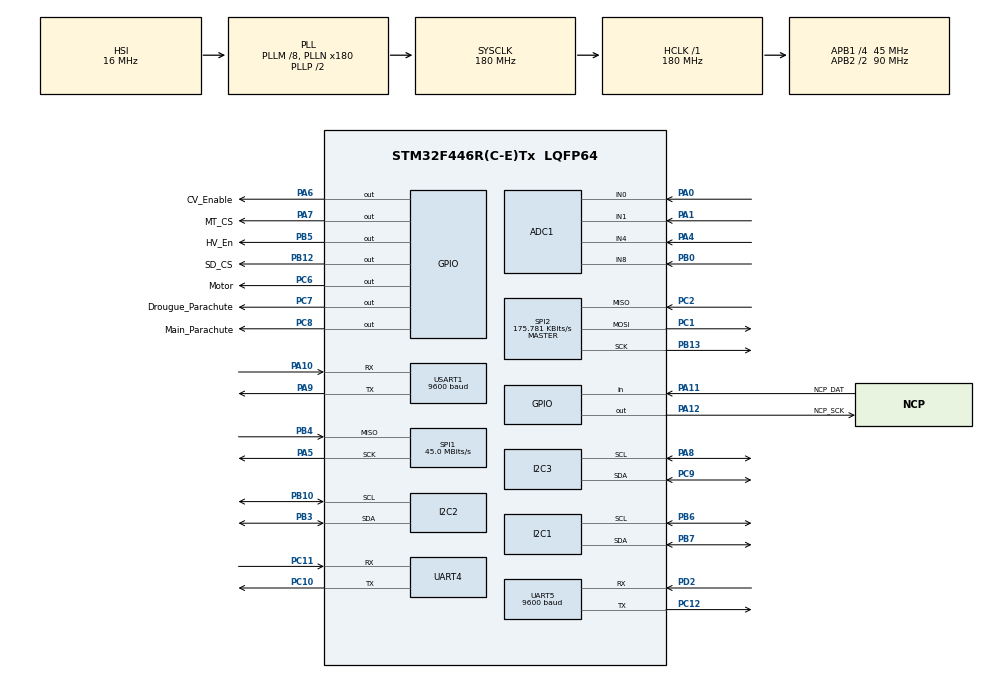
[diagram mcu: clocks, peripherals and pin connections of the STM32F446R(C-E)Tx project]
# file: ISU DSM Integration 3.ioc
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ADC1.Channel-0\#ChannelRegularConversion=ADC_CHANNEL_0
ADC1.Channel-1\#ChannelRegularConversion=ADC_CHANNEL_1
ADC1.Channel-2\#ChannelRegularConversion=ADC_CHANNEL_4
ADC1.Channel-3\#ChannelRegularConversion=ADC_CHANNEL_8
ADC1.ClockPrescaler=ADC_CLOCK_SYNC_PCLK_DIV8
ADC1.ContinuousConvMode=ENABLE
ADC1.DMAContinuousRequests=ENABLE
ADC1.NbrOfConversion=4
ADC1.NbrOfConversionFlag=1
ADC1.Rank-0\#ChannelRegularConversion=1
ADC1.Rank-1\#ChannelRegularConversion=2
ADC1.Rank-2\#ChannelRegularConversion=3
ADC1.Rank-3\#ChannelRegularConversion=4
ADC1.SamplingTime-0\#ChannelRegularConversion=ADC_SAMPLETIME_3CYCLES
ADC1.SamplingTime-1\#ChannelRegularConversion=ADC_SAMPLETIME_3CYCLES
ADC1.SamplingTime-2\#ChannelRegularConversion=ADC_SAMPLETIME_3CYCLES
ADC1.SamplingTime-3\#ChannelRegularConversion=ADC_SAMPLETIME_3CYCLES
ADC1.ScanConvMode=ENABLE
ADC1.master=1
Dma.ADC1.0.Direction=DMA_PERIPH_TO_MEMORY
Dma.ADC1.0.FIFOMode=DMA_FIFOMODE_DISABLE
Dma.ADC1.0.Instance=DMA2_Stream0
Dma.ADC1.0.MemDataAlignment=DMA_MDATAALIGN_HALFWORD
Dma.ADC1.0.MemInc=DMA_MINC_ENABLE
Dma.ADC1.0.Mode=DMA_CIRCULAR
Dma.ADC1.0.PeriphDataAlignment=DMA_PDATAALIGN_HALFWORD
Dma.ADC1.0.PeriphInc=DMA_PINC_DISABLE
Dma.ADC1.0.Priority=DMA_PRIORITY_LOW
Dma.Request0=ADC1
Dma.Request1=UART5_RX
Dma.Request2=UART5_TX
Dma.UART5_RX.1.Direction=DMA_PERIPH_TO_MEMORY
Dma.UART5_RX.1.FIFOMode=DMA_FIFOMODE_DISABLE
Dma.UART5_RX.1.Instance=DMA1_Stream0
Dma.UART5_RX.1.MemDataAlignment=DMA_MDATAALIGN_BYTE
Dma.UART5_RX.1.MemInc=DMA_MINC_ENABLE
Dma.UART5_RX.1.Mode=DMA_CIRCULAR
Dma.UART5_RX.1.PeriphDataAlignment=DMA_PDATAALIGN_BYTE
Dma.UART5_RX.1.PeriphInc=DMA_PINC_DISABLE
Dma.UART5_RX.1.Priority=DMA_PRIORITY_LOW
Dma.UART5_TX.2.Direction=DMA_MEMORY_TO_PERIPH
Dma.UART5_TX.2.FIFOMode=DMA_FIFOMODE_DISABLE
Dma.UART5_TX.2.Instance=DMA1_Stream7
Dma.UART5_TX.2.MemDataAlignment=DMA_MDATAALIGN_BYTE
Dma.UART5_TX.2.MemInc=DMA_MINC_ENABLE
Dma.UART5_TX.2.Mode=DMA_CIRCULAR
Dma.UART5_TX.2.PeriphDataAlignment=DMA_PDATAALIGN_BYTE
Dma.UART5_TX.2.PeriphInc=DMA_PINC_DISABLE
Dma.UART5_TX.2.Priority=DMA_PRIORITY_LOW
FATFS._MAX_SS=4096
FATFS._USE_LFN=1
Mcu.Family=STM32F4
Mcu.Name=STM32F446R(C-E)Tx
Mcu.Package=LQFP64
NVIC.DMA1_Stream0_IRQn=true\:0\:0\:false\:false\:true\:false\:true\:true
NVIC.DMA1_Stream7_IRQn=true\:0\:0\:false\:false\:true\:false\:true\:true
NVIC.DMA2_Stream0_IRQn=true\:0\:0\:false\:false\:true\:false\:true\:true
NVIC.PriorityGroup=NVIC_PRIORITYGROUP_4
NVIC.RCC_IRQn=true\:0\:0\:false\:false\:true\:true\:false\:true
NVIC.UART5_IRQn=true\:0\:0\:false\:false\:true\:true\:true\:true
NVIC.USART1_IRQn=true\:0\:0\:false\:false\:true\:true\:true\:true
PA0-WKUP.Signal=ADCx_IN0
PA1.Signal=ADCx_IN1
PA10.Mode=Asynchronous
PA10.Signal=USART1_RX
PA11.GPIO_Label=NCP_DAT
PA11.Signal=GPIO_Input
PA12.GPIO_Label=NCP_SCK
PA12.Signal=GPIO_Output
PA4.Signal=ADCx_IN4
PA5.Mode=RX_Only_Simplex_Unidirect_Master
PA5.Signal=SPI1_SCK
PA6.GPIO_Label=CV_Enable
PA6.GPIO_PuPd=GPIO_PULLDOWN
PA6.Signal=GPIO_Output
PA7.GPIO_Label=MT_CS
PA7.Signal=GPIO_Output
PA8.Mode=I2C
PA8.Signal=I2C3_SCL
PA9.Mode=Asynchronous
PA9.Signal=USART1_TX
PB0.Signal=ADCx_IN8
PB10.Mode=I2C
PB10.Signal=I2C2_SCL
PB12.GPIO_Label=SD_CS
PB12.Signal=GPIO_Output
PB13.Mode=Full_Duplex_Master
PB13.Signal=SPI2_SCK
PB3.Mode=I2C
PB3.Signal=I2C2_SDA
PB4.Mode=RX_Only_Simplex_Unidirect_Master
PB4.Signal=SPI1_MISO
PB5.GPIO_Label=HV_En
PB5.Signal=GPIO_Output
PB6.Mode=I2C
PB6.Signal=I2C1_SCL
PB7.Mode=I2C
PB7.Signal=I2C1_SDA
PC1.Mode=Full_Duplex_Master
PC1.Signal=SPI2_MOSI
PC10.Mode=Asynchronous
PC10.Signal=UART4_TX
PC11.Mode=Asynchronous
PC11.Signal=UART4_RX
PC12.Mode=Asynchronous
PC12.Signal=UART5_TX
PC14-OSC32_IN.Mode=LSE-External-Oscillator
PC14-OSC32_IN.Signal=RCC_OSC32_IN
PC15-OSC32_OUT.Mode=LSE-External-Oscillator
PC15-OSC32_OUT.Signal=RCC_OSC32_OUT
PC2.Mode=Full_Duplex_Master
PC2.Signal=SPI2_MISO
PC6.GPIO_Label=Motor
PC6.GPIO_PuPd=GPIO_PULLDOWN
PC6.Signal=GPIO_Output
PC7.GPIO_Label=Drougue_Parachute
PC7.GPIO_PuPd=GPIO_PULLDOWN
PC7.Signal=GPIO_Output
PC8.GPIO_Label=Main_Parachute
PC8.GPIO_PuPd=GPIO_PULLDOWN
PC8.Signal=GPIO_Output
PC9.Mode=I2C
PC9.Signal=I2C3_SDA
PD2.Mode=Asynchronous
PD2.Signal=UART5_RX
PH0-OSC_IN.Mode=HSE-External-Oscillator
PH0-OSC_IN.Signal=RCC_OSC_IN
PH1-OSC_OUT.Mode=HSE-External-Oscillator
PH1-OSC_OUT.Signal=RCC_OSC_OUT
ProjectManager.HeapSize=0x400
ProjectManager.StackSize=0x800
ProjectManager.TargetToolchain=STM32CubeIDE
RCC.AHBFreq_Value=180000000
RCC.APB1CLKDivider=RCC_HCLK_DIV4
RCC.APB1Freq_Value=45000000
RCC.APB1TimFreq_Value=90000000
RCC.APB2CLKDivider=RCC_HCLK_DIV2
RCC.APB2Freq_Value=90000000
RCC.APB2TimFreq_Value=180000000
RCC.CortexFreq_Value=180000000
RCC.HCLKFreq_Value=180000000
RCC.HSE_VALUE=8000000
RCC.PLLM=8
RCC.PLLN=180
RCC.SYSCLKFreq_VALUE=180000000
RCC.SYSCLKSource=RCC_SYSCLKSOURCE_PLLCLK
RCC.USBFreq_Value=180000000
RCC.VCOOutputFreq_Value=360000000
SH.ADCx_IN0.0=ADC1_IN0,IN0
SH.ADCx_IN1.0=ADC1_IN1,IN1
SH.ADCx_IN4.0=ADC1_IN4,IN4
SH.ADCx_IN8.0=ADC1_IN8,IN8
SPI1.CalculateBaudRate=45.0 MBits/s
SPI1.Direction=SPI_DIRECTION_2LINES_RXONLY
SPI1.Mode=SPI_MODE_MASTER
SPI1.VirtualType=VM_MASTER
SPI2.BaudRatePrescaler=SPI_BAUDRATEPRESCALER_256
SPI2.CalculateBaudRate=175.781 KBits/s
SPI2.Direction=SPI_DIRECTION_2LINES
SPI2.Mode=SPI_MODE_MASTER
SPI2.VirtualType=VM_MASTER
TIM1.Prescaler=45000
UART4.VirtualMode=Asynchronous
UART5.BaudRate=9600
UART5.VirtualMode=Asynchronous
USART1.BaudRate=9600
USART1.VirtualMode=VM_ASYNC
VP_FATFS_VS_Generic.Mode=User_defined
VP_TIM1_VS_ClockSourceINT.Mode=Internal
board=custom

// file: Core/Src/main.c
/* USER CODE BEGIN Header */
/**
  ******************************************************************************
  * @file           : main.c
  * @brief          : Main program body
  ******************************************************************************
  * @attention
  *
  * Copyright (c) 2023 STMicroelectronics.
  * All rights reserved.
  *
  * This software is licensed under terms that can be found in the LICENSE file
  * in the root directory of this software component.
  * If no LICENSE file comes with this software, it is provided AS-IS.
  *
  ******************************************************************************
  */
/* USER CODE END Header */
#include "main.h"
#include "fatfs.h"

/* USER CODE BEGIN Includes */
#include <stdbool.h>
#include "math.h"
#include "mpu6050.h"
#include "MAX6675.h"
#include "uartRingBuffer.h"
#include "NMEA.h"
#include "BMP180.h"
#include "HX710B.h"
#include "DataPacket.h"
#include "RTC.h"
#include "fatfs_sd.h"
#include "stdio.h"
/* USER CODE END Includes */

/* USER CODE BEGIN PD */
#define CV_En_Pin GPIO_PIN_6
/* USER CODE END PD */

ADC_HandleTypeDef hadc1;
DMA_HandleTypeDef hdma_adc1;

I2C_HandleTypeDef hi2c1;
I2C_HandleTypeDef hi2c2;
I2C_HandleTypeDef hi2c3;

SPI_HandleTypeDef hspi1;
SPI_HandleTypeDef hspi2;

TIM_HandleTypeDef htim1;

UART_HandleTypeDef huart4;
UART_HandleTypeDef huart5;
extern UART_HandleTypeDef huart1;
DMA_HandleTypeDef hdma_uart5_rx;
DMA_HandleTypeDef hdma_uart5_tx;

/* USER CODE BEGIN PV */
bool pds_flag = 1;
char rx_data[2];
char tx_data[2];
float Ax, Ay, Az, Gx, Gy, Gz, Avg1, Avg2;

uint8_t err_gyro = 0;

float CpmVoltage = 0.0;
float HVoltage = 0.0;
bool En_Voltage_ui=0;

float temperature;
uint16_t timer_val=0;

uint16_t dmaOut[4];

//Barometer_Sensor
float Temperature2;
float Pressure;
float Altitude;

//current_sensor 5A
uint16_t readValue5;
float rawVoltage5;
float current5;
float sensitivity5 = 0.185;
float adc_err5=1.052;

//current_sensor 20A
uint16_t readValue20;
float rawVoltage20;
float current20;
float sensitivity20 = 0.1;
float adc_err20=1.052;

//GPS Data
char GGA[100];
char RMC[100];

//Fall Detection
bool tilt=0;
bool fall=false;
bool pds=0;
GPSSTRUCT gpsData;

//Nose Cone Pressure
uint16_t NCPressure=0;

TIME_Handle time;
TIME_Handle timein;

uint8_t settime=0;

char TxBuff[150];
char tempbuff[6];

union Transmission trans1;

FATFS fs;  // file system
FIL fil; // File
FILINFO fno;
FRESULT fresult;  // result
UINT br, bw;  // File read/write count

/**** capacity related *****/
FATFS *pfs;
DWORD fre_clust;
uint32_t total, free_space;

#define BUFFER_SIZE 128
char buffer[BUFFER_SIZE];  // to store strings..
char rxbuffer[BUFFER_SIZE];

int writepos=0;

char tx_data[2];
/* USER CODE END PV */

void SystemClock_Config(void);
static void MX_GPIO_Init(void);
static void MX_DMA_Init(void);
static void MX_ADC1_Init(void);
static void MX_SPI1_Init(void);
static void MX_TIM1_Init(void);
static void MX_USART1_UART_Init(void);
static void MX_I2C1_Init(void);
static void MX_I2C2_Init(void);
static void MX_UART4_Init(void);
static void MX_I2C3_Init(void);
static void MX_SPI2_Init(void);
static void MX_UART5_Init(void);

/* USER CODE BEGIN 0 */

int bufsize (char *buf)
{
	int i=0;
	while (*buf++ != '\0') i++;
	return i;
}

void clear_buffer (void)
{
	for (int i=0; i<BUFFER_SIZE; i++) buffer[i] = '\0';
}
/* USER CODE END 0 */

int main(void)
{
  /* USER CODE BEGIN 1 */
	timein.seconds = 0;

  /* USER CODE END 1 */

  /* MCU Configuration--------------------------------------------------------*/

  /* Reset of all peripherals, Initializes the Flash interface and the Systick. */
  HAL_Init();

  /* Configure the system clock */
  SystemClock_Config();

  /* Initialize all configured peripherals */
  MX_GPIO_Init();
  MX_DMA_Init();
  MX_ADC1_Init();
  MX_SPI1_Init();
  MX_TIM1_Init();
  MX_USART1_UART_Init();
  MX_I2C1_Init();
  MX_I2C2_Init();
  MX_UART4_Init();
  MX_I2C3_Init();
  MX_SPI2_Init();
  MX_FATFS_Init();
  MX_UART5_Init();
  /* USER CODE BEGIN 2 */

  HAL_UART_Receive_DMA(&huart5,rx_data, sizeof(rx_data));

  HAL_ADC_Init(&hadc1);
  MPU6050_Init();
  HAL_ADC_Start_DMA(&hadc1, dmaOut, 4);
  BMP180_Start();

  Ringbuf_init();
  HAL_Delay(500);

  if(settime==1)
      Set_Time(timein.seconds, timein.minutes, timein.hour , timein.dayofweek, timein.dayofmonth, timein.month, timein.year);

  void current_sensor5()
  {
  	  readValue5 = dmaOut[1];
  	  rawVoltage5 = ((float) readValue5 * 3.3) / 4095 *adc_err5;
  	  trans1.tlm1.CPM_Current =(1 - rawVoltage5)/sensitivity5;
  }

  void current_sensor20()
  {
  	  readValue20 = dmaOut[2];
  	  rawVoltage20 = ((float) readValue20 * 3.3) / 4095 *adc_err20;
  	  trans1.tlm1.H_Current =(1 - rawVoltage20)/sensitivity20;
  }

  void barometer_sensor()
  {
  	  Temperature2 = BMP180_GetTemp();
  	  Pressure = BMP180_GetPress(0);
  	  trans1.tlm1.Altitude = BMP180_GetAlt(0);
  }
void isu_check()
{
	;
}
  strcpy(buffer,"Hello Duta'h\n");

  /* USER CODE END 2 */

  /* Infinite loop */
  /* USER CODE BEGIN WHILE */
  while (1)
  {
	  /*if(rx_data[0]=='T')
	  {
		 HAL_GPIO_WritePin(GPIOC, GPIO_PIN_6, 1);
				 HAL_GPIO_WritePin(GPIOC, GPIO_PIN_7, 1);
				 HAL_GPIO_WritePin(GPIOC, GPIO_PIN_8, 1);
	  }*/
	  switch(rx_data[0])
	  	  {
	      case 'N': //Initialization
		  memset(tx_data,'S',2);
	  	  HAL_UART_Transmit(&huart5, tx_data, sizeof(tx_data), 100);
	  	  break;
	  	  case 'K': //Standby
	  	  memset(tx_data,'J',2);
	  	  HAL_UART_Transmit(&huart5, tx_data, sizeof(tx_data), 100);
	  	  break;
	  	  case 'A': //Arming
	  	  memset(tx_data,'B',2);
	  	  HAL_UART_Transmit(&huart5, tx_data, sizeof(tx_data), 100);
	  	  isu_check();
	  	  break;
	  	  memset(tx_data,'D',2);
	  	  HAL_UART_Transmit(&huart5, tx_data, sizeof(tx_data), 100);
	  	  case 'I': //Launching
	  	  memset(tx_data,'L',2);
	  	  HAL_UART_Transmit(&huart5, tx_data, sizeof(tx_data), 100);
	  	  HAL_GPIO_WritePin(GPIOC, GPIO_PIN_6, 1);
	  	  memset(tx_data,'\0',2);
	  	  break;
	  	  case 'Y': //Kill_Switch
	  	  HAL_GPIO_WritePin(GPIOC, GPIO_PIN_6, 0);
	  	  memset(tx_data,'E',2);
	  	  HAL_UART_Transmit(&huart5, tx_data, sizeof(tx_data), 100);
	  	  break;
	  	  case 'F': //Error
	  	  memset(tx_data,'E',2);
	  	  HAL_UART_Transmit(&huart5, tx_data, sizeof(tx_data), 100);
	  	  break;
	  	  default:
	  	  memset(tx_data,'\0',2);
	  	  HAL_UART_Transmit(&huart5, tx_data, sizeof(tx_data), 100);
	  	  }
   HAL_Delay(5);
	  if(Wait_for("GGA")==1)
	  {
		  Copy_upto("*", GGA);
		  decodeGGA(GGA, &gpsData.ggastruct);
	  }
	  if (Wait_for("RMC")==1)
	  {
		  Copy_upto("*",RMC);
		  decodeRMC(RMC, &gpsData.rmcstruct);
	  }

	  trans1.tlm1.M_Temp=Max6675_Read_Temp();
	  barometer_sensor();
	  trans1.tlm1.NC_Press =readHX();

	  current_sensor5();
	  current_sensor20();

	  MPU6050_Read_Accel (&Ax, &Ay, &Az);
	  MPU6050_Read_Gyro(&Gx, &Gy, &Gz);
	  //Fall Detection
	 	  Avg1 = pow(pow(Ax,2)+pow(Ay,2)+pow(Az,2),0.5);
	 	  Avg2 = pow(pow(Gx,2)+pow(Gy,2)+pow(Gz,2),0.5);
	 	  tilt= HAL_GPIO_ReadPin(GPIOC, GPIO_PIN_3); //tilt_sensor
	 	  if(((Avg1 >= 1 && Avg2 >= 30) && tilt==0) || fall==true)
	 	  {
	 		  HAL_GPIO_WritePin(GPIOC, GPIO_PIN_8, GPIO_PIN_SET); //Trigger PDS(Main Parachute)
	 		  HAL_GPIO_WritePin(GPIOA, GPIO_PIN_5, 1);
	 	  }
	 	  else
	 	  {
	 	  }
	 	  HAL_Delay (100);  // wait for a while
	 	  //PDS_read_sensor
	 	  pds = HAL_GPIO_ReadPin(GPIOC, GPIO_PIN_5);
	 	  if(pds==0)
	 	  {
	 		  HAL_GPIO_WritePin(GPIOC, GPIO_PIN_8, GPIO_PIN_RESET); //Trigger PDS(Main Parachute)
	 		  if(pds_flag==1){
	 			  memset(tx_data,'R',2);
	 			  HAL_UART_Transmit(&huart5, tx_data, sizeof(tx_data), 100);
	 			  HAL_Delay(3000);
	 			  memset(tx_data,'\0',2);
	 			  pds_flag=0;
	 		  }
	 	  }
	  //HAL_Delay(250);
	  trans1.tlm1.Ax=Ax;
	  trans1.tlm1.Ay=Ay;
	  trans1.tlm1.Az=Az;
	  trans1.tlm1.Gx=Gx;
	  trans1.tlm1.Gy=Gy;
	  trans1.tlm1.Gz=Gz;

	  HAL_GPIO_WritePin(GPIOA, CV_En_Pin, 1);
	  trans1.tlm1.CPM_Voltage = dmaOut[0]*(5.0/4096.0);
	  HAL_GPIO_WritePin(HV_En_GPIO_Port, HV_En_Pin, 1);
	  trans1.tlm1.H_Voltage=dmaOut[3]*(9.36/4096);

	  HAL_Delay(100);
	  Get_Time();
		trans1.tlm1.seconds=time.seconds;
		trans1.tlm1.minutes=time.minutes;
		trans1.tlm1.hour=time.hour;
		trans1.tlm1.dayofmonth=time.dayofmonth;
		trans1.tlm1.month=time.month;
		trans1.tlm1.year=time.year;

		fresult = f_mount(&fs, "/", 1);
		HAL_Delay(500);
		fresult = f_open(&fil, "testfile.txt", FA_OPEN_ALWAYS | FA_READ | FA_WRITE);
		//	  memset(TxBuff,"\0",150);

	  for(int i=0; i<23; i++)
	  {

		  memset(tempbuff,'\0',6);
		  gcvt(trans1.dataframe[i],4,tempbuff);
		  //strcat(TxBuff,tempbuff);
		  strcat(tempbuff,",");
		  HAL_UART_Transmit(&huart4, tempbuff, strlen(tempbuff), 100);
		  if(i==22) strcat(tempbuff, "\n");

		  f_lseek(&fil,writepos);
		  fresult = f_write(&fil, tempbuff, bufsize(tempbuff), &bw);
		  writepos+=bufsize(tempbuff);
	  }
//		HAL_UART_Transmit(&huart4, "20-11-2023,", 11, 100);
//		memset(tempbuff,'\0',6);
//		gcvt(trans1.tlm1.Ax,4,tempbuff);
//		strcat(tempbuff,",");
//		HAL_UART_Transmit(&huart4, tempbuff, strlen(tempbuff), 100);
//		memset(tempbuff,'\0',6);
//		strcat(tempbuff,",");
//		gcvt(trans1.tlm1.Ay,4,tempbuff);
//		strcat(tempbuff,",");
//		HAL_UART_Transmit(&huart4, tempbuff, strlen(tempbuff), 100);
//		memset(tempbuff,'\0',6);
//		gcvt(trans1.tlm1.Az,4,tempbuff);
//		strcat(tempbuff,",");
//		HAL_UART_Transmit(&huart4, tempbuff, strlen(tempbuff), 100);
//		HAL_UART_Transmit(&huart4, "9.25,", 6, 100);
//		HAL_UART_Transmit(&huart4, "0.01,", 6, 100);
//		gcvt(trans1.tlm1.CPM_Voltage,4,tempbuff);
//		strcat(tempbuff,",");
//		HAL_UART_Transmit(&huart4, tempbuff, strlen(tempbuff), 100);
//		gcvt(trans1.tlm1.CPM_Current,4,tempbuff);
//		strcat(tempbuff,",");
//		HAL_UART_Transmit(&huart4, tempbuff, strlen(tempbuff), 100);
//		HAL_UART_Transmit(&huart4, "22.4,", 7, 100);
//		memset(tempbuff,'\0',6);
//		gcvt(trans1.tlm1.Altitude,4,tempbuff);
//		strcat(tempbuff,",");
//		HAL_UART_Transmit(&huart4, tempbuff, strlen(tempbuff), 100);
//		memset(tempbuff,'\0',6);
//		gcvt(Pressure,4,tempbuff);
//		strcat(tempbuff,",");
//		HAL_UART_Transmit(&huart4, tempbuff, strlen(tempbuff), 100);
//		HAL_UART_Transmit(&huart4, "0,", 3, 100);
//		memset(tempbuff,'\0',6);
//		gcvt(trans1.tlm1.Gx,4,tempbuff);
//		strcat(tempbuff,",");
//		HAL_UART_Transmit(&huart4, tempbuff, strlen(tempbuff), 100);
//		memset(tempbuff,'\0',6);
//		gcvt(trans1.tlm1.Gy,4,tempbuff);
//		strcat(tempbuff,",");
//		HAL_UART_Transmit(&huart4, tempbuff, strlen(tempbuff), 100);
//		memset(tempbuff,'\0',6);
//		gcvt(trans1.tlm1.Gz,4,tempbuff);
//		strcat(tempbuff,",");
//		HAL_UART_Transmit(&huart4, tempbuff, strlen(tempbuff), 100);
//		HAL_UART_Transmit(&huart4, "0,", 3, 100);
//		HAL_UART_Transmit(&huart4, "0", 3, 100);

	  f_close(&fil);
	  fresult = f_mount(NULL, "/", 1);

	  HAL_UART_Transmit(&huart4, "\n", 1, 100);

	  /*fresult = f_lseek(&fil, writepos);
	  fresult = f_write(&fil, strw, bufsize(strw), &bw);
	  f_close(&fil);
	  writepos+=sizeof(strw);

	  fresult = f_open(&fil, "testfile.txt", FA_READ);
	  f_read (&fil, rxbuffer, f_size(&fil), &br);
	  f_close(&fil);
	  fresult = f_mount(NULL, "/", 1);*/

	  HAL_Delay(100);

    /* USER CODE END WHILE */

  }
}

void SystemClock_Config(void)
{
  RCC_OscInitTypeDef RCC_OscInitStruct = {0};
  RCC_ClkInitTypeDef RCC_ClkInitStruct = {0};

  /** Configure the main internal regulator output voltage
  */
  __HAL_RCC_PWR_CLK_ENABLE();
  __HAL_PWR_VOLTAGESCALING_CONFIG(PWR_REGULATOR_VOLTAGE_SCALE1);

  /** Initializes the RCC Oscillators according to the specified parameters
  * in the RCC_OscInitTypeDef structure.
  */
  RCC_OscInitStruct.OscillatorType = RCC_OSCILLATORTYPE_HSI;
  RCC_OscInitStruct.HSIState = RCC_HSI_ON;
  RCC_OscInitStruct.HSICalibrationValue = RCC_HSICALIBRATION_DEFAULT;
  RCC_OscInitStruct.PLL.PLLState = RCC_PLL_ON;
  RCC_OscInitStruct.PLL.PLLSource = RCC_PLLSOURCE_HSI;
  RCC_OscInitStruct.PLL.PLLM = 8;
  RCC_OscInitStruct.PLL.PLLN = 180;
  RCC_OscInitStruct.PLL.PLLP = RCC_PLLP_DIV2;
  RCC_OscInitStruct.PLL.PLLQ = 2;
  RCC_OscInitStruct.PLL.PLLR = 2;
  if (HAL_RCC_OscConfig(&RCC_OscInitStruct) != HAL_OK)
  {
    Error_Handler();
  }

  /** Activate the Over-Drive mode
  */
  if (HAL_PWREx_EnableOverDrive() != HAL_OK)
  {
    Error_Handler();
  }

  /** Initializes the CPU, AHB and APB buses clocks
  */
  RCC_ClkInitStruct.ClockType = RCC_CLOCKTYPE_HCLK|RCC_CLOCKTYPE_SYSCLK
                              |RCC_CLOCKTYPE_PCLK1|RCC_CLOCKTYPE_PCLK2;
  RCC_ClkInitStruct.SYSCLKSource = RCC_SYSCLKSOURCE_PLLCLK;
  RCC_ClkInitStruct.AHBCLKDivider = RCC_SYSCLK_DIV1;
  RCC_ClkInitStruct.APB1CLKDivider = RCC_HCLK_DIV4;
  RCC_ClkInitStruct.APB2CLKDivider = RCC_HCLK_DIV2;

  if (HAL_RCC_ClockConfig(&RCC_ClkInitStruct, FLASH_LATENCY_5) != HAL_OK)
  {
    Error_Handler();
  }
}

static void MX_ADC1_Init(void)
{

  ADC_ChannelConfTypeDef sConfig = {0};

  /** Configure the global features of the ADC (Clock, Resolution, Data Alignment and number of conversion)
  */
  hadc1.Instance = ADC1;
  hadc1.Init.ClockPrescaler = ADC_CLOCK_SYNC_PCLK_DIV8;
  hadc1.Init.Resolution = ADC_RESOLUTION_12B;
  hadc1.Init.ScanConvMode = ENABLE;
  hadc1.Init.ContinuousConvMode = ENABLE;
  hadc1.Init.DiscontinuousConvMode = DISABLE;
  hadc1.Init.ExternalTrigConvEdge = ADC_EXTERNALTRIGCONVEDGE_NONE;
  hadc1.Init.ExternalTrigConv = ADC_SOFTWARE_START;
  hadc1.Init.DataAlign = ADC_DATAALIGN_RIGHT;
  hadc1.Init.NbrOfConversion = 4;
  hadc1.Init.DMAContinuousRequests = ENABLE;
  hadc1.Init.EOCSelection = ADC_EOC_SINGLE_CONV;
  if (HAL_ADC_Init(&hadc1) != HAL_OK)
  {
    Error_Handler();
  }

  /** Configure for the selected ADC regular channel its corresponding rank in the sequencer and its sample time.
  */
  sConfig.Channel = ADC_CHANNEL_0;
  sConfig.Rank = 1;
  sConfig.SamplingTime = ADC_SAMPLETIME_3CYCLES;
  if (HAL_ADC_ConfigChannel(&hadc1, &sConfig) != HAL_OK)
  {
    Error_Handler();
  }

  /** Configure for the selected ADC regular channel its corresponding rank in the sequencer and its sample time.
  */
  sConfig.Channel = ADC_CHANNEL_1;
  sConfig.Rank = 2;
  if (HAL_ADC_ConfigChannel(&hadc1, &sConfig) != HAL_OK)
  {
    Error_Handler();
  }

  /** Configure for the selected ADC regular channel its corresponding rank in the sequencer and its sample time.
  */
  sConfig.Channel = ADC_CHANNEL_4;
  sConfig.Rank = 3;
  if (HAL_ADC_ConfigChannel(&hadc1, &sConfig) != HAL_OK)
  {
    Error_Handler();
  }

  /** Configure for the selected ADC regular channel its corresponding rank in the sequencer and its sample time.
  */
  sConfig.Channel = ADC_CHANNEL_8;
  sConfig.Rank = 4;
  if (HAL_ADC_ConfigChannel(&hadc1, &sConfig) != HAL_OK)
  {
    Error_Handler();
  }

}

static void MX_I2C1_Init(void)
{

  hi2c1.Instance = I2C1;
  hi2c1.Init.ClockSpeed = 100000;
  hi2c1.Init.DutyCycle = I2C_DUTYCYCLE_2;
  hi2c1.Init.OwnAddress1 = 0;
  hi2c1.Init.AddressingMode = I2C_ADDRESSINGMODE_7BIT;
  hi2c1.Init.DualAddressMode = I2C_DUALADDRESS_DISABLE;
  hi2c1.Init.OwnAddress2 = 0;
  hi2c1.Init.GeneralCallMode = I2C_GENERALCALL_DISABLE;
  hi2c1.Init.NoStretchMode = I2C_NOSTRETCH_DISABLE;
  if (HAL_I2C_Init(&hi2c1) != HAL_OK)
  {
    Error_Handler();
  }

}

static void MX_I2C2_Init(void)
{

  hi2c2.Instance = I2C2;
  hi2c2.Init.ClockSpeed = 100000;
  hi2c2.Init.DutyCycle = I2C_DUTYCYCLE_2;
  hi2c2.Init.OwnAddress1 = 0;
  hi2c2.Init.AddressingMode = I2C_ADDRESSINGMODE_7BIT;
  hi2c2.Init.DualAddressMode = I2C_DUALADDRESS_DISABLE;
  hi2c2.Init.OwnAddress2 = 0;
  hi2c2.Init.GeneralCallMode = I2C_GENERALCALL_DISABLE;
  hi2c2.Init.NoStretchMode = I2C_NOSTRETCH_DISABLE;
  if (HAL_I2C_Init(&hi2c2) != HAL_OK)
  {
    Error_Handler();
  }

}

static void MX_I2C3_Init(void)
{

  hi2c3.Instance = I2C3;
  hi2c3.Init.ClockSpeed = 100000;
  hi2c3.Init.DutyCycle = I2C_DUTYCYCLE_2;
  hi2c3.Init.OwnAddress1 = 0;
  hi2c3.Init.AddressingMode = I2C_ADDRESSINGMODE_7BIT;
  hi2c3.Init.DualAddressMode = I2C_DUALADDRESS_DISABLE;
  hi2c3.Init.OwnAddress2 = 0;
  hi2c3.Init.GeneralCallMode = I2C_GENERALCALL_DISABLE;
  hi2c3.Init.NoStretchMode = I2C_NOSTRETCH_DISABLE;
  if (HAL_I2C_Init(&hi2c3) != HAL_OK)
  {
    Error_Handler();
  }

}

static void MX_SPI1_Init(void)
{

  /* SPI1 parameter configuration*/
  hspi1.Instance = SPI1;
  hspi1.Init.Mode = SPI_MODE_MASTER;
  hspi1.Init.Direction = SPI_DIRECTION_2LINES_RXONLY;
  hspi1.Init.DataSize = SPI_DATASIZE_8BIT;
  hspi1.Init.CLKPolarity = SPI_POLARITY_LOW;
  hspi1.Init.CLKPhase = SPI_PHASE_1EDGE;
  hspi1.Init.NSS = SPI_NSS_SOFT;
  hspi1.Init.BaudRatePrescaler = SPI_BAUDRATEPRESCALER_2;
  hspi1.Init.FirstBit = SPI_FIRSTBIT_MSB;
  hspi1.Init.TIMode = SPI_TIMODE_DISABLE;
  hspi1.Init.CRCCalculation = SPI_CRCCALCULATION_DISABLE;
  hspi1.Init.CRCPolynomial = 10;
  if (HAL_SPI_Init(&hspi1) != HAL_OK)
  {
    Error_Handler();
  }

}

static void MX_SPI2_Init(void)
{

  /* SPI2 parameter configuration*/
  hspi2.Instance = SPI2;
  hspi2.Init.Mode = SPI_MODE_MASTER;
  hspi2.Init.Direction = SPI_DIRECTION_2LINES;
  hspi2.Init.DataSize = SPI_DATASIZE_8BIT;
  hspi2.Init.CLKPolarity = SPI_POLARITY_LOW;
  hspi2.Init.CLKPhase = SPI_PHASE_1EDGE;
  hspi2.Init.NSS = SPI_NSS_SOFT;
  hspi2.Init.BaudRatePrescaler = SPI_BAUDRATEPRESCALER_256;
  hspi2.Init.FirstBit = SPI_FIRSTBIT_MSB;
  hspi2.Init.TIMode = SPI_TIMODE_DISABLE;
  hspi2.Init.CRCCalculation = SPI_CRCCALCULATION_DISABLE;
  hspi2.Init.CRCPolynomial = 10;
  if (HAL_SPI_Init(&hspi2) != HAL_OK)
  {
    Error_Handler();
  }

}

static void MX_TIM1_Init(void)
{

  TIM_ClockConfigTypeDef sClockSourceConfig = {0};
  TIM_MasterConfigTypeDef sMasterConfig = {0};

  htim1.Instance = TIM1;
  htim1.Init.Prescaler = 45000;
  htim1.Init.CounterMode = TIM_COUNTERMODE_UP;
  htim1.Init.Period = 65535;
  htim1.Init.ClockDivision = TIM_CLOCKDIVISION_DIV1;
  htim1.Init.RepetitionCounter = 0;
  htim1.Init.AutoReloadPreload = TIM_AUTORELOAD_PRELOAD_DISABLE;
  if (HAL_TIM_Base_Init(&htim1) != HAL_OK)
  {
    Error_Handler();
  }
  sClockSourceConfig.ClockSource = TIM_CLOCKSOURCE_INTERNAL;
  if (HAL_TIM_ConfigClockSource(&htim1, &sClockSourceConfig) != HAL_OK)
  {
    Error_Handler();
  }
  sMasterConfig.MasterOutputTrigger = TIM_TRGO_RESET;
  sMasterConfig.MasterSlaveMode = TIM_MASTERSLAVEMODE_DISABLE;
  if (HAL_TIMEx_MasterConfigSynchronization(&htim1, &sMasterConfig) != HAL_OK)
  {
    Error_Handler();
  }

}

static void MX_UART4_Init(void)
{

  huart4.Instance = UART4;
  huart4.Init.BaudRate = 115200;
  huart4.Init.WordLength = UART_WORDLENGTH_8B;
  huart4.Init.StopBits = UART_STOPBITS_1;
  huart4.Init.Parity = UART_PARITY_NONE;
  huart4.Init.Mode = UART_MODE_TX_RX;
  huart4.Init.HwFlowCtl = UART_HWCONTROL_NONE;
  huart4.Init.OverSampling = UART_OVERSAMPLING_16;
  if (HAL_UART_Init(&huart4) != HAL_OK)
  {
    Error_Handler();
  }

}

static void MX_UART5_Init(void)
{

  huart5.Instance = UART5;
  huart5.Init.BaudRate = 9600;
  huart5.Init.WordLength = UART_WORDLENGTH_8B;
  huart5.Init.StopBits = UART_STOPBITS_1;
  huart5.Init.Parity = UART_PARITY_NONE;
  huart5.Init.Mode = UART_MODE_TX_RX;
  huart5.Init.HwFlowCtl = UART_HWCONTROL_NONE;
  huart5.Init.OverSampling = UART_OVERSAMPLING_16;
  if (HAL_UART_Init(&huart5) != HAL_OK)
  {
    Error_Handler();
  }

}

static void MX_USART1_UART_Init(void)
{

  huart1.Instance = USART1;
  huart1.Init.BaudRate = 9600;
  huart1.Init.WordLength = UART_WORDLENGTH_8B;
  huart1.Init.StopBits = UART_STOPBITS_1;
  huart1.Init.Parity = UART_PARITY_NONE;
  huart1.Init.Mode = UART_MODE_TX_RX;
  huart1.Init.HwFlowCtl = UART_HWCONTROL_NONE;
  huart1.Init.OverSampling = UART_OVERSAMPLING_16;
  if (HAL_UART_Init(&huart1) != HAL_OK)
  {
    Error_Handler();
  }

}

static void MX_DMA_Init(void)
{

  /* DMA controller clock enable */
  __HAL_RCC_DMA2_CLK_ENABLE();
  __HAL_RCC_DMA1_CLK_ENABLE();

  /* DMA interrupt init */
  /* DMA1_Stream0_IRQn interrupt configuration */
  HAL_NVIC_SetPriority(DMA1_Stream0_IRQn, 0, 0);
  HAL_NVIC_EnableIRQ(DMA1_Stream0_IRQn);
  /* DMA1_Stream7_IRQn interrupt configuration */
  HAL_NVIC_SetPriority(DMA1_Stream7_IRQn, 0, 0);
  HAL_NVIC_EnableIRQ(DMA1_Stream7_IRQn);
  /* DMA2_Stream0_IRQn interrupt configuration */
  HAL_NVIC_SetPriority(DMA2_Stream0_IRQn, 0, 0);
  HAL_NVIC_EnableIRQ(DMA2_Stream0_IRQn);

}

static void MX_GPIO_Init(void)
{
  GPIO_InitTypeDef GPIO_InitStruct = {0};

  /* GPIO Ports Clock Enable */
  __HAL_RCC_GPIOC_CLK_ENABLE();
  __HAL_RCC_GPIOH_CLK_ENABLE();
  __HAL_RCC_GPIOA_CLK_ENABLE();
  __HAL_RCC_GPIOB_CLK_ENABLE();
  __HAL_RCC_GPIOD_CLK_ENABLE();

  /*Configure GPIO pin Output Level */
  HAL_GPIO_WritePin(GPIOA, CV_Enable_Pin|MT_CS_Pin|NCP_SCK_Pin, GPIO_PIN_RESET);

  /*Configure GPIO pin Output Level */
  HAL_GPIO_WritePin(GPIOB, SD_CS_Pin|HV_En_Pin, GPIO_PIN_RESET);

  /*Configure GPIO pin Output Level */
  HAL_GPIO_WritePin(GPIOC, Motor_Pin|Drougue_Parachute_Pin|Main_Parachute_Pin, GPIO_PIN_RESET);

  /*Configure GPIO pin : Tilt_Sensor_Pin */
  GPIO_InitStruct.Pin = Tilt_Sensor_Pin;
  GPIO_InitStruct.Mode = GPIO_MODE_INPUT;
  GPIO_InitStruct.Pull = GPIO_NOPULL;
  HAL_GPIO_Init(Tilt_Sensor_GPIO_Port, &GPIO_InitStruct);

  /*Configure GPIO pin : CV_Enable_Pin */
  GPIO_InitStruct.Pin = CV_Enable_Pin;
  GPIO_InitStruct.Mode = GPIO_MODE_OUTPUT_PP;
  GPIO_InitStruct.Pull = GPIO_PULLDOWN;
  GPIO_InitStruct.Speed = GPIO_SPEED_FREQ_LOW;
  HAL_GPIO_Init(CV_Enable_GPIO_Port, &GPIO_InitStruct);

  /*Configure GPIO pins : MT_CS_Pin NCP_SCK_Pin */
  GPIO_InitStruct.Pin = MT_CS_Pin|NCP_SCK_Pin;
  GPIO_InitStruct.Mode = GPIO_MODE_OUTPUT_PP;
  GPIO_InitStruct.Pull = GPIO_NOPULL;
  GPIO_InitStruct.Speed = GPIO_SPEED_FREQ_LOW;
  HAL_GPIO_Init(GPIOA, &GPIO_InitStruct);

  /*Configure GPIO pin : Read_PDS_Pin */
  GPIO_InitStruct.Pin = Read_PDS_Pin;
  GPIO_InitStruct.Mode = GPIO_MODE_INPUT;
  GPIO_InitStruct.Pull = GPIO_PULLDOWN;
  HAL_GPIO_Init(Read_PDS_GPIO_Port, &GPIO_InitStruct);

  /*Configure GPIO pins : SD_CS_Pin HV_En_Pin */
  GPIO_InitStruct.Pin = SD_CS_Pin|HV_En_Pin;
  GPIO_InitStruct.Mode = GPIO_MODE_OUTPUT_PP;
  GPIO_InitStruct.Pull = GPIO_NOPULL;
  GPIO_InitStruct.Speed = GPIO_SPEED_FREQ_LOW;
  HAL_GPIO_Init(GPIOB, &GPIO_InitStruct);

  /*Configure GPIO pins : Motor_Pin Drougue_Parachute_Pin Main_Parachute_Pin */
  GPIO_InitStruct.Pin = Motor_Pin|Drougue_Parachute_Pin|Main_Parachute_Pin;
  GPIO_InitStruct.Mode = GPIO_MODE_OUTPUT_PP;
  GPIO_InitStruct.Pull = GPIO_PULLDOWN;
  GPIO_InitStruct.Speed = GPIO_SPEED_FREQ_LOW;
  HAL_GPIO_Init(GPIOC, &GPIO_InitStruct);

  /*Configure GPIO pin : NCP_DAT_Pin */
  GPIO_InitStruct.Pin = NCP_DAT_Pin;
  GPIO_InitStruct.Mode = GPIO_MODE_INPUT;
  GPIO_InitStruct.Pull = GPIO_NOPULL;
  HAL_GPIO_Init(NCP_DAT_GPIO_Port, &GPIO_InitStruct);

}

/* USER CODE BEGIN 4 */
int _write(int file, char *ptr, int len)
{
	int DataIdx;

	for (DataIdx = 0; DataIdx < len; DataIdx++)
	{
		ITM_SendChar(*ptr++);
	}
	return len;
}
/* USER CODE END 4 */

void Error_Handler(void)
{
  __disable_irq();
  while (1)
  {
  }
}
